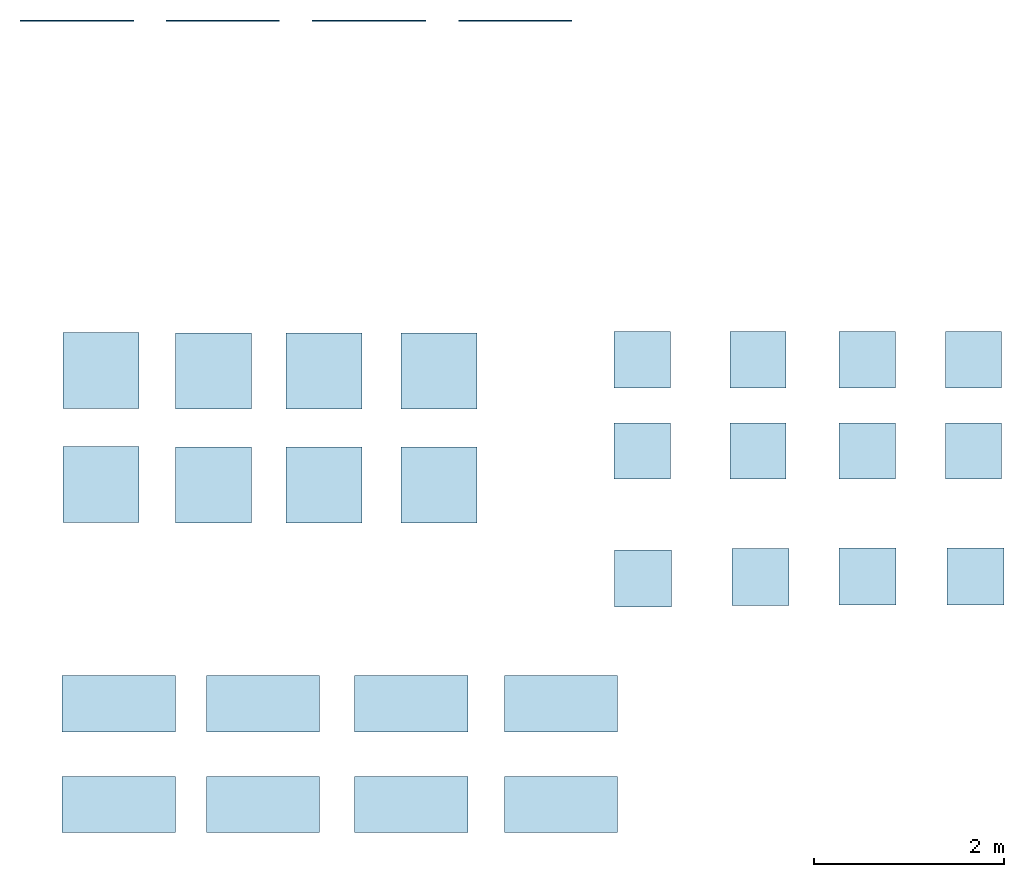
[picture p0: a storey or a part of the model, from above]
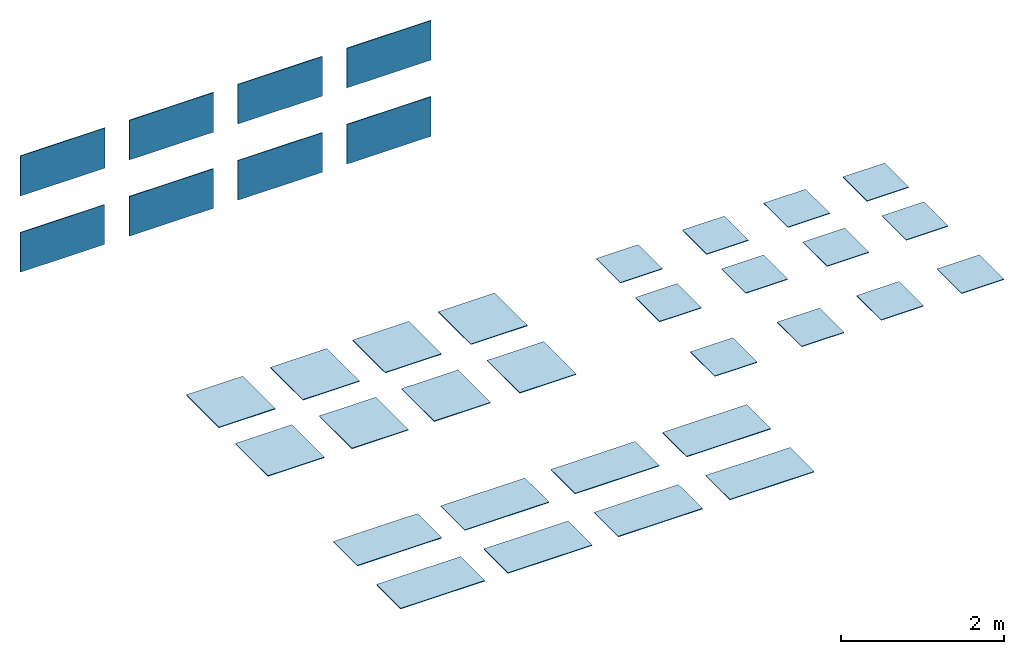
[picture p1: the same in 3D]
Properties of the parts of a building model (IFC2X3)

# File
Description: ViewDefinition [CoordinationView_V2.0]
File name: Número de proyecto
Time: 2017-10-19T16:17:04
Written by: The EXPRESS Data Manager Version 5.02.0100.07 : 28 Aug 2013
Made in: 20160225_1515(x64) - Exporter 17.0.416.0 - Alternate UI 17.12.14.0
Comment: STEP Physical File produced by: The EXPRESS Data Manager Version 5.02.0100.07 : 28 Aug 2013 * Module: EDMstepFileFactory/EDMstandAlone * Creation date: Thu Oct 19 16:17:04 2017 * Host: REVIT * Database: C:\Users\corte\AppData\Local\Temp\{3F6E3162-8A38-4D94-924C-B81E332C5563}\ifc * Database version: 5507 * Database creation date: Thu Oct 19 16:17:02 2017 * Schema: IFC2X3 * Model: DataRepository.ifc * Model creation date: Thu Oct 19 16:17:02 2017 * Header model: DataRepository.ifc_HeaderModel * Header model creation date: Thu Oct 19 16:17:02 2017 * EDMuser: sdai-user * EDMgroup: sdai-group * License ID and type: 5605 : Permanent license. Expiry date: * EDMstepFileFactory options: 020000

# IfcProject, Número de proyecto
LongName: Nombre de proyecto; Phase: Estado de proyecto

# IfcSite, Default
RefLatitude: 40, 25, 0, 86975; RefLongitude: -3, -42, -1, -243858; RefElevation: 0 m

# IfcBuilding
Pset_BuildingCommon - NumberOfStoreys: 2

# IfcBuildingStorey (2)
Name | LongName | Elevation (m)
PORTOFINO FLOOR TILES | PORTOFINO FLOOR TILES | 0
Nivel 2 | Nivel 2 | 3

# IfcSlab: Suelo:VIVES PORTOFINO CEMENTO 60X60, Suelo:VIVES PORTOFINO CEMENTO 60X60:159050
In: PORTOFINO FLOOR TILES
PredefinedType: FLOOR; Material: VIVES PORTOFINO CEMENTO 60x60 0.01 m
Pset_SlabCommon - IsExternal: no; LoadBearing: yes; PitchAngle: 0 deg; Reference: VIVES PORTOFINO CEMENTO 60X60; ThermalTransmittance: 150 kg/K/s3
Pset_ManufacturerTypeInformation - Manufacturer: VIVES Azulejos y Gres S.A.

# IfcSlab: Suelo:VIVES PORTOFINO CREMA 60X60, Suelo:VIVES PORTOFINO CREMA 60X60:159194
In: PORTOFINO FLOOR TILES
PredefinedType: FLOOR; Material: VIVES PORTOFINO CREMA 60x60 0.01 m
Pset_SlabCommon - IsExternal: no; LoadBearing: yes; PitchAngle: 0 deg; Reference: VIVES PORTOFINO CREMA 60X60; ThermalTransmittance: 150 kg/K/s3
Pset_ManufacturerTypeInformation - Manufacturer: VIVES Azulejos y Gres S.A.

# IfcSlab: Suelo:VIVES PORTOFINO GRAFITO 60X60, Suelo:VIVES PORTOFINO GRAFITO 60X60:159130
In: PORTOFINO FLOOR TILES
PredefinedType: FLOOR; Material: VIVES PORTOFINO GRAFITO 60x60 0.01 m
Pset_SlabCommon - IsExternal: no; LoadBearing: yes; PitchAngle: 0 deg; Reference: VIVES PORTOFINO GRAFITO 60X60; ThermalTransmittance: 150 kg/K/s3
Pset_ManufacturerTypeInformation - Manufacturer: VIVES Azulejos y Gres S.A.

# IfcSlab: Suelo:VIVES PORTOFINO HUMO 60X60, Suelo:VIVES PORTOFINO HUMO 60X60:159255
In: PORTOFINO FLOOR TILES
PredefinedType: FLOOR; Material: VIVES PORTOFINO HUMO 60x60 0.01 m
Pset_SlabCommon - IsExternal: no; LoadBearing: yes; PitchAngle: 0 deg; Reference: VIVES PORTOFINO HUMO 60X60; ThermalTransmittance: 150 kg/K/s3
Pset_ManufacturerTypeInformation - Manufacturer: VIVES Azulejos y Gres S.A.

# IfcSlab: Suelo:VIVES PORTOFINO-R CEMENTO 59,3X59,3, Suelo:VIVES PORTOFINO-R CEMENTO 59,3X59,3:159692
In: PORTOFINO FLOOR TILES
PredefinedType: FLOOR; Material: VIVES PORTOFINO-R CEMENTO 59,3x59,3 0.01 m
Pset_SlabCommon - IsExternal: no; LoadBearing: yes; PitchAngle: 0 deg; Reference: VIVES PORTOFINO-R CEMENTO 59,3X59,3; ThermalTransmittance: 150 kg/K/s3
Pset_ManufacturerTypeInformation - Manufacturer: VIVES Azulejos y Gres S.A.

# IfcSlab: Suelo:VIVES PORTOFINO-R CEMENTO 59,3x119,3, Suelo:VIVES PORTOFINO-R CEMENTO 59,3x119,3:155036
In: PORTOFINO FLOOR TILES
PredefinedType: FLOOR; Material: VIVES PORTOFINO-R CEMENTO 59,3x119,3 0.011 m
Pset_SlabCommon - Reference: VIVES PORTOFINO-R CEMENTO 59,3x119,3; IsExternal: no; LoadBearing: yes; ThermalTransmittance: 136.364 kg/K/s3; PitchAngle: 0 deg
Pset_ManufacturerTypeInformation - Manufacturer: VIVES Azulejos y Gres S.A.

# IfcSlab: Suelo:VIVES PORTOFINO-R CEMENTO 80X80, Suelo:VIVES PORTOFINO-R CEMENTO 80X80:158260
In: PORTOFINO FLOOR TILES
PredefinedType: FLOOR; Material: VIVES PORTOFINO-R CEMENTO 80x80 0.011 m
Pset_SlabCommon - IsExternal: no; LoadBearing: yes; PitchAngle: 0 deg; Reference: VIVES PORTOFINO-R CEMENTO 80X80; ThermalTransmittance: 136.364 kg/K/s3
Pset_ManufacturerTypeInformation - Manufacturer: VIVES Azulejos y Gres S.A.

# IfcSlab: Suelo:VIVES PORTOFINO-R CREMA 59,3X59,3, Suelo:VIVES PORTOFINO-R CREMA 59,3X59,3:159708
In: PORTOFINO FLOOR TILES
PredefinedType: FLOOR; Material: VIVES PORTOFINO-R CREMA 59.3x59.3 0.01 m
Pset_SlabCommon - IsExternal: no; LoadBearing: yes; PitchAngle: 0 deg; Reference: VIVES PORTOFINO-R CREMA 59,3X59,3; ThermalTransmittance: 150 kg/K/s3
Pset_ManufacturerTypeInformation - Manufacturer: VIVES Azulejos y Gres S.A.

# IfcSlab: Suelo:VIVES PORTOFINO-R CREMA 59,3x119,3, Suelo:VIVES PORTOFINO-R CREMA 59,3x119,3:158392
In: PORTOFINO FLOOR TILES
PredefinedType: FLOOR; Material: VIVES PORTOFINO-R CREMA 59,3x119,3 0.011 m
Pset_SlabCommon - IsExternal: no; LoadBearing: yes; PitchAngle: 0 deg; Reference: VIVES PORTOFINO-R CREMA 59,3x119,3; ThermalTransmittance: 136.364 kg/K/s3
Pset_ManufacturerTypeInformation - Manufacturer: VIVES Azulejos y Gres S.A.

# IfcSlab: Suelo:VIVES PORTOFINO-R CREMA 80X80, Suelo:VIVES PORTOFINO-R CREMA 80X80:155343
In: PORTOFINO FLOOR TILES
PredefinedType: FLOOR; Material: VIVES PORTOFINO-R CREMA 80x80 0.011 m
Pset_SlabCommon - IsExternal: no; LoadBearing: yes; PitchAngle: 0 deg; Reference: VIVES PORTOFINO-R CREMA 80X80; ThermalTransmittance: 136.364 kg/K/s3
Pset_ManufacturerTypeInformation - Manufacturer: VIVES Azulejos y Gres S.A.

# IfcSlab: Suelo:VIVES PORTOFINO-R GRAFITO 59,3X59,3, Suelo:VIVES PORTOFINO-R GRAFITO 59,3X59,3:159700
In: PORTOFINO FLOOR TILES
PredefinedType: FLOOR; Material: VIVES PORTOFINO-R GRAFITO 59.3x59.3 0.01 m
Pset_SlabCommon - IsExternal: no; LoadBearing: yes; PitchAngle: 0 deg; Reference: VIVES PORTOFINO-R GRAFITO 59,3X59,3; ThermalTransmittance: 150 kg/K/s3
Pset_ManufacturerTypeInformation - Manufacturer: VIVES Azulejos y Gres S.A.

# IfcSlab: Suelo:VIVES PORTOFINO-R GRAFITO 59,3x119,3, Suelo:VIVES PORTOFINO-R GRAFITO 59,3x119,3:158298
In: PORTOFINO FLOOR TILES
PredefinedType: FLOOR; Material: VIVES PORTOFINO-R GRAFITO 59.3x119.3 0.011 m
Pset_SlabCommon - IsExternal: no; LoadBearing: yes; PitchAngle: 0 deg; Reference: VIVES PORTOFINO-R GRAFITO 59,3x119,3; ThermalTransmittance: 136.364 kg/K/s3
Pset_ManufacturerTypeInformation - Manufacturer: VIVES Azulejos y Gres S.A.

# IfcSlab: Suelo:VIVES PORTOFINO-R GRAFITO 80X80, Suelo:VIVES PORTOFINO-R GRAFITO 80X80:155271
In: PORTOFINO FLOOR TILES
PredefinedType: FLOOR; Material: VIVES PORTOFINO-R GRAFITO 80x80 0.011 m
Pset_SlabCommon - IsExternal: no; LoadBearing: yes; PitchAngle: 0 deg; Reference: VIVES PORTOFINO-R GRAFITO 80X80; ThermalTransmittance: 136.364 kg/K/s3
Pset_ManufacturerTypeInformation - Manufacturer: VIVES Azulejos y Gres S.A.

# IfcSlab: Suelo:VIVES PORTOFINO-R HUMO 59,3X59,3, Suelo:VIVES PORTOFINO-R HUMO 59,3X59,3:159716
In: PORTOFINO FLOOR TILES
PredefinedType: FLOOR; Material: VIVES PORTOFINO-R HUMO 59.3x59.3 0.01 m
Pset_SlabCommon - IsExternal: no; LoadBearing: yes; PitchAngle: 0 deg; Reference: VIVES PORTOFINO-R HUMO 59,3X59,3; ThermalTransmittance: 150 kg/K/s3
Pset_ManufacturerTypeInformation - Manufacturer: VIVES Azulejos y Gres S.A.

# IfcSlab: Suelo:VIVES PORTOFINO-R HUMO 59,3x119,3, Suelo:VIVES PORTOFINO-R HUMO 59,3x119,3:158453
In: PORTOFINO FLOOR TILES
PredefinedType: FLOOR; Material: VIVES PORTOFINO-R HUMO 59,3x119,3 0.011 m
Pset_SlabCommon - IsExternal: no; LoadBearing: yes; PitchAngle: 0 deg; Reference: VIVES PORTOFINO-R HUMO 59,3x119,3; ThermalTransmittance: 136.364 kg/K/s3
Pset_ManufacturerTypeInformation - Manufacturer: VIVES Azulejos y Gres S.A.

# IfcSlab: Suelo:VIVES PORTOFINO-R HUMO 80X80, Suelo:VIVES PORTOFINO-R HUMO 80X80:155394
In: PORTOFINO FLOOR TILES
PredefinedType: FLOOR; Material: VIVES PORTOFINO-R HUMO 80x80 0.011 m
Pset_SlabCommon - IsExternal: no; LoadBearing: yes; PitchAngle: 0 deg; Reference: VIVES PORTOFINO-R HUMO 80X80; ThermalTransmittance: 136.364 kg/K/s3
Pset_ManufacturerTypeInformation - Manufacturer: VIVES Azulejos y Gres S.A.

# IfcSlab: Suelo:VIVES PORTOFINO-SPR CEMENTO 59,3X59,3, Suelo:VIVES PORTOFINO-SPR CEMENTO 59,3X59,3:159317
In: PORTOFINO FLOOR TILES
PredefinedType: FLOOR; Material: VIVES PORTOFINO-SPR CEMENTO 59.3x59.3 0.01 m
Pset_SlabCommon - IsExternal: no; LoadBearing: yes; PitchAngle: 0 deg; Reference: VIVES PORTOFINO-SPR CEMENTO 59,3X59,3; ThermalTransmittance: 150 kg/K/s3
Pset_ManufacturerTypeInformation - Manufacturer: VIVES Azulejos y Gres S.A.

# IfcSlab: Suelo:VIVES PORTOFINO-SPR CEMENTO 59,3x119,3, Suelo:VIVES PORTOFINO-SPR CEMENTO 59,3x119,3:158524
In: PORTOFINO FLOOR TILES
PredefinedType: FLOOR; Material: VIVES PORTOFINO-SPR CEMENTO 59.3x119.3 0.011 m
Pset_SlabCommon - IsExternal: no; LoadBearing: yes; PitchAngle: 0 deg; Reference: VIVES PORTOFINO-SPR CEMENTO 59,3x119,3; ThermalTransmittance: 136.364 kg/K/s3
Pset_ManufacturerTypeInformation - Manufacturer: VIVES Azulejos y Gres S.A.

# IfcSlab: Suelo:VIVES PORTOFINO-SPR CEMENTO 80X80, Suelo:VIVES PORTOFINO-SPR CEMENTO 80X80:158841
In: PORTOFINO FLOOR TILES
PredefinedType: FLOOR; Material: VIVES PORTOFINO-SPR CEMENTO 80x80 0.011 m
Pset_SlabCommon - IsExternal: no; LoadBearing: yes; PitchAngle: 0 deg; Reference: VIVES PORTOFINO-SPR CEMENTO 80X80; ThermalTransmittance: 136.364 kg/K/s3
Pset_ManufacturerTypeInformation - Manufacturer: VIVES Azulejos y Gres S.A.

# IfcSlab: Suelo:VIVES PORTOFINO-SPR CREMA 59,3X59,3, Suelo:VIVES PORTOFINO-SPR CREMA 59,3X59,3:159617
In: PORTOFINO FLOOR TILES
PredefinedType: FLOOR; Material: VIVES PORTOFINO-SPR CREMA 59.3x59.3 0.01 m
Pset_SlabCommon - IsExternal: no; LoadBearing: yes; PitchAngle: 0 deg; Reference: VIVES PORTOFINO-SPR CREMA 59,3X59,3; ThermalTransmittance: 150 kg/K/s3
Pset_ManufacturerTypeInformation - Manufacturer: VIVES Azulejos y Gres S.A.

# IfcSlab: Suelo:VIVES PORTOFINO-SPR CREMA 59,3x119,3, Suelo:VIVES PORTOFINO-SPR CREMA 59,3x119,3:158677
In: PORTOFINO FLOOR TILES
PredefinedType: FLOOR; Material: VIVES PORTOFINO-SPR CREMA 59.3x119.3 0.011 m
Pset_SlabCommon - IsExternal: no; LoadBearing: yes; PitchAngle: 0 deg; Reference: VIVES PORTOFINO-SPR CREMA 59,3x119,3; ThermalTransmittance: 136.364 kg/K/s3
Pset_ManufacturerTypeInformation - Manufacturer: VIVES Azulejos y Gres S.A.

# IfcSlab: Suelo:VIVES PORTOFINO-SPR CREMA 80X80, Suelo:VIVES PORTOFINO-SPR CREMA 80X80:158824
In: PORTOFINO FLOOR TILES
PredefinedType: FLOOR; Material: VIVES PORTOFINO-SPR CREMA 80x80 0.011 m
Pset_SlabCommon - IsExternal: no; LoadBearing: yes; PitchAngle: 0 deg; Reference: VIVES PORTOFINO-SPR CREMA 80X80; ThermalTransmittance: 136.364 kg/K/s3
Pset_ManufacturerTypeInformation - Manufacturer: VIVES Azulejos y Gres S.A.

# IfcSlab: Suelo:VIVES PORTOFINO-SPR GRAFITO 59,3X59,3, Suelo:VIVES PORTOFINO-SPR GRAFITO 59,3X59,3:159586
In: PORTOFINO FLOOR TILES
PredefinedType: FLOOR; Material: VIVES PORTOFINO-SPR GRAFITO 59.3x59.3 0.01 m
Pset_SlabCommon - IsExternal: no; LoadBearing: yes; PitchAngle: 0 deg; Reference: VIVES PORTOFINO-SPR GRAFITO 59,3X59,3; ThermalTransmittance: 150 kg/K/s3
Pset_ManufacturerTypeInformation - Manufacturer: VIVES Azulejos y Gres S.A.

# IfcSlab: Suelo:VIVES PORTOFINO-SPR GRAFITO 59,3x119,3, Suelo:VIVES PORTOFINO-SPR GRAFITO 59,3x119,3:158610
In: PORTOFINO FLOOR TILES
PredefinedType: FLOOR; Material: VIVES PORTOFINO-SPR GRAFITO 59.3x119.3 0.011 m
Pset_SlabCommon - IsExternal: no; LoadBearing: yes; PitchAngle: 0 deg; Reference: VIVES PORTOFINO-SPR GRAFITO 59,3x119,3; ThermalTransmittance: 136.364 kg/K/s3
Pset_ManufacturerTypeInformation - Manufacturer: VIVES Azulejos y Gres S.A.

# IfcSlab: Suelo:VIVES PORTOFINO-SPR GRAFITO 80X80, Suelo:VIVES PORTOFINO-SPR GRAFITO 80X80:158817
In: PORTOFINO FLOOR TILES
PredefinedType: FLOOR; Material: VIVES PORTOFINO-SPR GRAFITO 80x80 0.011 m
Pset_SlabCommon - IsExternal: no; LoadBearing: yes; PitchAngle: 0 deg; Reference: VIVES PORTOFINO-SPR GRAFITO 80X80; ThermalTransmittance: 136.364 kg/K/s3
Pset_ManufacturerTypeInformation - Manufacturer: VIVES Azulejos y Gres S.A.

# IfcSlab: Suelo:VIVES PORTOFINO-SPR HUMO 59,3X59,3, Suelo:VIVES PORTOFINO-SPR HUMO 59,3X59,3:159630
In: PORTOFINO FLOOR TILES
PredefinedType: FLOOR; Material: VIVES PORTOFINO-SPR HUMO 59.3x59.3 0.01 m
Pset_SlabCommon - IsExternal: no; LoadBearing: yes; PitchAngle: 0 deg; Reference: VIVES PORTOFINO-SPR HUMO 59,3X59,3; ThermalTransmittance: 150 kg/K/s3
Pset_ManufacturerTypeInformation - Manufacturer: VIVES Azulejos y Gres S.A.

# IfcSlab: Suelo:VIVES PORTOFINO-SPR HUMO 59,3x119,3, Suelo:VIVES PORTOFINO-SPR HUMO 59,3x119,3:158740
In: PORTOFINO FLOOR TILES
PredefinedType: FLOOR; Material: VIVES PORTOFINO-SPR HUMO 59.3x119.3 0.011 m
Pset_SlabCommon - IsExternal: no; LoadBearing: yes; PitchAngle: 0 deg; Reference: VIVES PORTOFINO-SPR HUMO 59,3x119,3; ThermalTransmittance: 136.364 kg/K/s3
Pset_ManufacturerTypeInformation - Manufacturer: VIVES Azulejos y Gres S.A.

# IfcSlab: Suelo:VIVES PORTOFINO-SPR HUMO 80X80, Suelo:VIVES PORTOFINO-SPR HUMO 80X80:158831
In: PORTOFINO FLOOR TILES
PredefinedType: FLOOR; Material: VIVES PORTOFINO-SPR HUMO 80x80 0.011 m
Pset_SlabCommon - IsExternal: no; LoadBearing: yes; PitchAngle: 0 deg; Reference: VIVES PORTOFINO-SPR HUMO 80X80; ThermalTransmittance: 136.364 kg/K/s3
Pset_ManufacturerTypeInformation - Manufacturer: VIVES Azulejos y Gres S.A.

# IfcWallStandardCase: Muro básico:VIVES - PORTOFINO CEMENTO 60X60, Muro básico:VIVES - PORTOFINO CEMENTO 60X60:169846
In: Nivel 2
Type - PredefinedType: STANDARD; Material: VIVES PORTOFINO CEMENTO 60x60 0.01 m
Pset_WallCommon - IsExternal: no; LoadBearing: no; ExtendToStructure: no; Reference: VIVES - PORTOFINO CEMENTO 60X60; ThermalTransmittance: 150 kg/K/s3
Pset_ManufacturerTypeInformation - Manufacturer: VIVES Azulejos y Gres S.A.

# IfcWallStandardCase: Muro básico:VIVES - PORTOFINO CREMA 60X60, Muro básico:VIVES - PORTOFINO CREMA 60X60:169848
In: Nivel 2
Type - PredefinedType: STANDARD; Material: VIVES PORTOFINO CREMA 60x60 0.01 m
Pset_WallCommon - IsExternal: no; LoadBearing: no; ExtendToStructure: no; Reference: VIVES - PORTOFINO CREMA 60X60; ThermalTransmittance: 150 kg/K/s3
Pset_ManufacturerTypeInformation - Manufacturer: VIVES Azulejos y Gres S.A.

# IfcWallStandardCase: Muro básico:VIVES - PORTOFINO GRAFITO 60X60, Muro básico:VIVES - PORTOFINO GRAFITO 60X60:169847
In: Nivel 2
Type - PredefinedType: STANDARD; Material: VIVES PORTOFINO GRAFITO 60x60 0.01 m
Pset_WallCommon - IsExternal: no; LoadBearing: no; ExtendToStructure: no; Reference: VIVES - PORTOFINO GRAFITO 60X60; ThermalTransmittance: 150 kg/K/s3
Pset_ManufacturerTypeInformation - Manufacturer: VIVES Azulejos y Gres S.A.

# IfcWallStandardCase: Muro básico:VIVES - PORTOFINO HUMO 60X60, Muro básico:VIVES - PORTOFINO HUMO 60X60:169849
In: Nivel 2
Type - PredefinedType: STANDARD; Material: VIVES PORTOFINO HUMO 60x60 0.01 m
Pset_WallCommon - IsExternal: no; LoadBearing: no; ExtendToStructure: no; Reference: VIVES - PORTOFINO HUMO 60X60; ThermalTransmittance: 150 kg/K/s3
Pset_ManufacturerTypeInformation - Manufacturer: VIVES Azulejos y Gres S.A.

# IfcWallStandardCase: Muro básico:VIVES - PORTOFINO-R CEMENTO 59,3X119,3, Muro básico:VIVES - PORTOFINO-R CEMENTO 59,3X119,3:170386
In: PORTOFINO FLOOR TILES
Type - PredefinedType: STANDARD; Material: VIVES PORTOFINO-R CEMENTO 59,3x119,3 0.011 m
Pset_WallCommon - IsExternal: no; LoadBearing: no; ExtendToStructure: no; Reference: VIVES - PORTOFINO-R CEMENTO 59,3X119,3; ThermalTransmittance: 136.364 kg/K/s3
Pset_ManufacturerTypeInformation - Manufacturer: VIVES Azulejos y Gres S.A.

# IfcWallStandardCase: Muro básico:VIVES - PORTOFINO-R CEMENTO 59,3X59,3, Muro básico:VIVES - PORTOFINO-R CEMENTO 59,3X59,3:170481
In: Nivel 2
Type - PredefinedType: STANDARD; Material: VIVES PORTOFINO-R CEMENTO 59,3x59,3 0.01 m
Pset_WallCommon - IsExternal: no; LoadBearing: no; ExtendToStructure: no; Reference: VIVES - PORTOFINO-R CEMENTO 59,3X59,3; ThermalTransmittance: 150 kg/K/s3
Pset_ManufacturerTypeInformation - Manufacturer: VIVES Azulejos y Gres S.A.

# IfcWallStandardCase: Muro básico:VIVES - PORTOFINO-R CEMENTO 80X80, Muro básico:VIVES - PORTOFINO-R CEMENTO 80X80:170533
In: Nivel 2
Type - PredefinedType: STANDARD; Material: VIVES PORTOFINO-R CEMENTO 80x80 0.011 m
Pset_WallCommon - IsExternal: no; LoadBearing: no; ExtendToStructure: no; Reference: VIVES - PORTOFINO-R CEMENTO 80X80; ThermalTransmittance: 136.364 kg/K/s3
Pset_ManufacturerTypeInformation - Manufacturer: VIVES Azulejos y Gres S.A.

# IfcWallStandardCase: Muro básico:VIVES - PORTOFINO-R CREMA 59,3X119,3, Muro básico:VIVES - PORTOFINO-R CREMA 59,3X119,3:170388
In: PORTOFINO FLOOR TILES
Type - PredefinedType: STANDARD; Material: VIVES PORTOFINO-R CREMA 59,3x119,3 0.011 m
Pset_WallCommon - IsExternal: no; LoadBearing: no; ExtendToStructure: no; Reference: VIVES - PORTOFINO-R CREMA 59,3X119,3; ThermalTransmittance: 136.364 kg/K/s3
Pset_ManufacturerTypeInformation - Manufacturer: VIVES Azulejos y Gres S.A.

# IfcWallStandardCase: Muro básico:VIVES - PORTOFINO-R CREMA 59,3X59,3, Muro básico:VIVES - PORTOFINO-R CREMA 59,3X59,3:170479
In: Nivel 2
Type - PredefinedType: STANDARD; Material: VIVES PORTOFINO-R CREMA 59.3x59.3 0.01 m
Pset_WallCommon - IsExternal: no; LoadBearing: no; ExtendToStructure: no; Reference: VIVES - PORTOFINO-R CREMA 59,3X59,3; ThermalTransmittance: 150 kg/K/s3
Pset_ManufacturerTypeInformation - Manufacturer: VIVES Azulejos y Gres S.A.

# IfcWallStandardCase: Muro básico:VIVES - PORTOFINO-R CREMA 80X80, Muro básico:VIVES - PORTOFINO-R CREMA 80X80:170535
In: Nivel 2
Type - PredefinedType: STANDARD; Material: VIVES PORTOFINO-R CREMA 80x80 0.011 m
Pset_WallCommon - IsExternal: no; LoadBearing: no; ExtendToStructure: no; Reference: VIVES - PORTOFINO-R CREMA 80X80; ThermalTransmittance: 136.364 kg/K/s3
Pset_ManufacturerTypeInformation - Manufacturer: VIVES Azulejos y Gres S.A.

# IfcWallStandardCase: Muro básico:VIVES - PORTOFINO-R GRAFITO 59,3X119,3, Muro básico:VIVES - PORTOFINO-R GRAFITO 59,3X119,3:170387
In: PORTOFINO FLOOR TILES
Type - PredefinedType: STANDARD; Material: VIVES PORTOFINO-R GRAFITO 59.3x119.3 0.011 m
Pset_WallCommon - IsExternal: no; LoadBearing: no; ExtendToStructure: no; Reference: VIVES - PORTOFINO-R GRAFITO 59,3X119,3; ThermalTransmittance: 136.364 kg/K/s3
Pset_ManufacturerTypeInformation - Manufacturer: VIVES Azulejos y Gres S.A.

# IfcWallStandardCase: Muro básico:VIVES - PORTOFINO-R GRAFITO 59,3X59,3, Muro básico:VIVES - PORTOFINO-R GRAFITO 59,3X59,3:170480
In: Nivel 2
Type - PredefinedType: STANDARD; Material: VIVES PORTOFINO-R GRAFITO 59.3x59.3 0.01 m
Pset_WallCommon - IsExternal: no; LoadBearing: no; ExtendToStructure: no; Reference: VIVES - PORTOFINO-R GRAFITO 59,3X59,3; ThermalTransmittance: 150 kg/K/s3
Pset_ManufacturerTypeInformation - Manufacturer: VIVES Azulejos y Gres S.A.

# IfcWallStandardCase: Muro básico:VIVES - PORTOFINO-R GRAFITO 80X80, Muro básico:VIVES - PORTOFINO-R GRAFITO 80X80:170534
In: Nivel 2
Type - PredefinedType: STANDARD; Material: VIVES PORTOFINO-R GRAFITO 80x80 0.011 m
Pset_WallCommon - IsExternal: no; LoadBearing: no; ExtendToStructure: no; Reference: VIVES - PORTOFINO-R GRAFITO 80X80; ThermalTransmittance: 136.364 kg/K/s3
Pset_ManufacturerTypeInformation - Manufacturer: VIVES Azulejos y Gres S.A.

# IfcWallStandardCase: Muro básico:VIVES - PORTOFINO-R HUMO 59,3X119,3, Muro básico:VIVES - PORTOFINO-R HUMO 59,3X119,3:170389
In: PORTOFINO FLOOR TILES
Type - PredefinedType: STANDARD; Material: VIVES PORTOFINO-R HUMO 59,3x119,3 0.011 m
Pset_WallCommon - IsExternal: no; LoadBearing: no; ExtendToStructure: no; Reference: VIVES - PORTOFINO-R HUMO 59,3X119,3; ThermalTransmittance: 136.364 kg/K/s3
Pset_ManufacturerTypeInformation - Manufacturer: VIVES Azulejos y Gres S.A.

# IfcWallStandardCase: Muro básico:VIVES - PORTOFINO-R HUMO 59,3X59,3, Muro básico:VIVES - PORTOFINO-R HUMO 59,3X59,3:170478
In: Nivel 2
Type - PredefinedType: STANDARD; Material: VIVES PORTOFINO-R HUMO 59.3x59.3 0.01 m
Pset_WallCommon - IsExternal: no; LoadBearing: no; ExtendToStructure: no; Reference: VIVES - PORTOFINO-R HUMO 59,3X59,3; ThermalTransmittance: 150 kg/K/s3
Pset_ManufacturerTypeInformation - Manufacturer: VIVES Azulejos y Gres S.A.

# IfcWallStandardCase: Muro básico:VIVES - PORTOFINO-R HUMO 80X80, Muro básico:VIVES - PORTOFINO-R HUMO 80X80:170536
In: Nivel 2
Type - PredefinedType: STANDARD; Material: VIVES PORTOFINO-R HUMO 80x80 0.011 m
Pset_WallCommon - IsExternal: no; LoadBearing: no; ExtendToStructure: no; Reference: VIVES - PORTOFINO-R HUMO 80X80; ThermalTransmittance: 136.364 kg/K/s3
Pset_ManufacturerTypeInformation - Manufacturer: VIVES Azulejos y Gres S.A.

# IfcWallStandardCase: Muro básico:VIVES - PORTOFINO-SPR CEMENTO 59,3X119,3, Muro básico:VIVES - PORTOFINO-SPR CEMENTO 59,3X119,3:164180
In: PORTOFINO FLOOR TILES
Type - PredefinedType: STANDARD; Material: VIVES PORTOFINO-SPR CEMENTO 59.3x119.3 0.011 m
Pset_WallCommon - IsExternal: no; Reference: VIVES - PORTOFINO-SPR CEMENTO 59,3X119,3; LoadBearing: no; ExtendToStructure: no; ThermalTransmittance: 136.364 kg/K/s3
Pset_ManufacturerTypeInformation - Manufacturer: VIVES Azulejos y Gres S.A.

# IfcWallStandardCase: Muro básico:VIVES - PORTOFINO-SPR CEMENTO 59,3X59,3, Muro básico:VIVES - PORTOFINO-SPR CEMENTO 59,3X59,3:170485
In: Nivel 2
Type - PredefinedType: STANDARD; Material: VIVES PORTOFINO-SPR CEMENTO 59.3x59.3 0.01 m
Pset_WallCommon - IsExternal: no; LoadBearing: no; ExtendToStructure: no; Reference: VIVES - PORTOFINO-SPR CEMENTO 59,3X59,3; ThermalTransmittance: 150 kg/K/s3
Pset_ManufacturerTypeInformation - Manufacturer: VIVES Azulejos y Gres S.A.

# IfcWallStandardCase: Muro básico:VIVES - PORTOFINO-SPR CEMENTO 80X80, Muro básico:VIVES - PORTOFINO-SPR CEMENTO 80X80:170537
In: Nivel 2
Type - PredefinedType: STANDARD; Material: VIVES PORTOFINO-SPR CEMENTO 80x80 0.011 m
Pset_WallCommon - IsExternal: no; LoadBearing: no; ExtendToStructure: no; Reference: VIVES - PORTOFINO-SPR CEMENTO 80X80; ThermalTransmittance: 136.364 kg/K/s3
Pset_ManufacturerTypeInformation - Manufacturer: VIVES Azulejos y Gres S.A.

# IfcWallStandardCase: Muro básico:VIVES - PORTOFINO-SPR CREMA 59,3X119,3, Muro básico:VIVES - PORTOFINO-SPR CREMA 59,3X119,3:164336
In: PORTOFINO FLOOR TILES
Type - PredefinedType: STANDARD; Material: VIVES PORTOFINO-SPR CREMA 59.3x119.3 0.011 m
Pset_WallCommon - IsExternal: no; LoadBearing: no; ExtendToStructure: no; Reference: VIVES - PORTOFINO-SPR CREMA 59,3X119,3; ThermalTransmittance: 136.364 kg/K/s3
Pset_ManufacturerTypeInformation - Manufacturer: VIVES Azulejos y Gres S.A.

# IfcWallStandardCase: Muro básico:VIVES - PORTOFINO-SPR CREMA 59,3X59,3, Muro básico:VIVES - PORTOFINO-SPR CREMA 59,3X59,3:170483
In: Nivel 2
Type - PredefinedType: STANDARD; Material: VIVES PORTOFINO-SPR CREMA 59.3x59.3 0.01 m
Pset_WallCommon - IsExternal: no; LoadBearing: no; ExtendToStructure: no; Reference: VIVES - PORTOFINO-SPR CREMA 59,3X59,3; ThermalTransmittance: 150 kg/K/s3
Pset_ManufacturerTypeInformation - Manufacturer: VIVES Azulejos y Gres S.A.

# IfcWallStandardCase: Muro básico:VIVES - PORTOFINO-SPR CREMA 80X80, Muro básico:VIVES - PORTOFINO-SPR CREMA 80X80:170539
In: Nivel 2
Type - PredefinedType: STANDARD; Material: VIVES PORTOFINO-SPR CREMA 80x80 0.011 m
Pset_WallCommon - IsExternal: no; LoadBearing: no; ExtendToStructure: no; Reference: VIVES - PORTOFINO-SPR CREMA 80X80; ThermalTransmittance: 136.364 kg/K/s3
Pset_ManufacturerTypeInformation - Manufacturer: VIVES Azulejos y Gres S.A.

# IfcWallStandardCase: Muro básico:VIVES - PORTOFINO-SPR GRAFITO 59,3X119,3, Muro básico:VIVES - PORTOFINO-SPR GRAFITO 59,3X119,3:164254
In: PORTOFINO FLOOR TILES
Type - PredefinedType: STANDARD; Material: VIVES PORTOFINO-SPR GRAFITO 59.3x119.3 0.011 m
Pset_WallCommon - IsExternal: no; LoadBearing: no; ExtendToStructure: no; Reference: VIVES - PORTOFINO-SPR GRAFITO 59,3X119,3; ThermalTransmittance: 136.364 kg/K/s3
Pset_ManufacturerTypeInformation - Manufacturer: VIVES Azulejos y Gres S.A.

# IfcWallStandardCase: Muro básico:VIVES - PORTOFINO-SPR GRAFITO 59,3X59,3, Muro básico:VIVES - PORTOFINO-SPR GRAFITO 59,3X59,3:170484
In: Nivel 2
Type - PredefinedType: STANDARD; Material: VIVES PORTOFINO-SPR GRAFITO 59.3x59.3 0.01 m
Pset_WallCommon - IsExternal: no; LoadBearing: no; ExtendToStructure: no; Reference: VIVES - PORTOFINO-SPR GRAFITO 59,3X59,3; ThermalTransmittance: 150 kg/K/s3
Pset_ManufacturerTypeInformation - Manufacturer: VIVES Azulejos y Gres S.A.

# IfcWallStandardCase: Muro básico:VIVES - PORTOFINO-SPR GRAFITO 80X80, Muro básico:VIVES - PORTOFINO-SPR GRAFITO 80X80:170538
In: Nivel 2
Type - PredefinedType: STANDARD; Material: VIVES PORTOFINO-SPR GRAFITO 80x80 0.011 m
Pset_WallCommon - IsExternal: no; LoadBearing: no; ExtendToStructure: no; Reference: VIVES - PORTOFINO-SPR GRAFITO 80X80; ThermalTransmittance: 136.364 kg/K/s3
Pset_ManufacturerTypeInformation - Manufacturer: VIVES Azulejos y Gres S.A.

# IfcWallStandardCase: Muro básico:VIVES - PORTOFINO-SPR HUMO 59,3X119,3, Muro básico:VIVES - PORTOFINO-SPR HUMO 59,3X119,3:164409
In: PORTOFINO FLOOR TILES
Type - PredefinedType: STANDARD; Material: VIVES PORTOFINO-SPR HUMO 59.3x119.3 0.011 m
Pset_WallCommon - IsExternal: no; LoadBearing: no; ExtendToStructure: no; Reference: VIVES - PORTOFINO-SPR HUMO 59,3X119,3; ThermalTransmittance: 136.364 kg/K/s3
Pset_ManufacturerTypeInformation - Manufacturer: VIVES Azulejos y Gres S.A.

# IfcWallStandardCase: Muro básico:VIVES - PORTOFINO-SPR HUMO 59,3X59,3, Muro básico:VIVES - PORTOFINO-SPR HUMO 59,3X59,3:170482
In: Nivel 2
Type - PredefinedType: STANDARD; Material: VIVES PORTOFINO-SPR HUMO 59.3x59.3 0.01 m
Pset_WallCommon - IsExternal: no; LoadBearing: no; ExtendToStructure: no; Reference: VIVES - PORTOFINO-SPR HUMO 59,3X59,3; ThermalTransmittance: 150 kg/K/s3
Pset_ManufacturerTypeInformation - Manufacturer: VIVES Azulejos y Gres S.A.

# IfcWallStandardCase: Muro básico:VIVES - PORTOFINO-SPR HUMO 80X80, Muro básico:VIVES - PORTOFINO-SPR HUMO 80X80:170540
In: Nivel 2
Type - PredefinedType: STANDARD; Material: VIVES PORTOFINO-SPR HUMO 80x80 0.011 m
Pset_WallCommon - IsExternal: no; LoadBearing: no; ExtendToStructure: no; Reference: VIVES - PORTOFINO-SPR HUMO 80X80; ThermalTransmittance: 136.364 kg/K/s3
Pset_ManufacturerTypeInformation - Manufacturer: VIVES Azulejos y Gres S.A.
